VERSION 5.7 ;
  NOWIREEXTENSIONATPIN ON ;
  DIVIDERCHAR "/" ;
  BUSBITCHARS "[]" ;
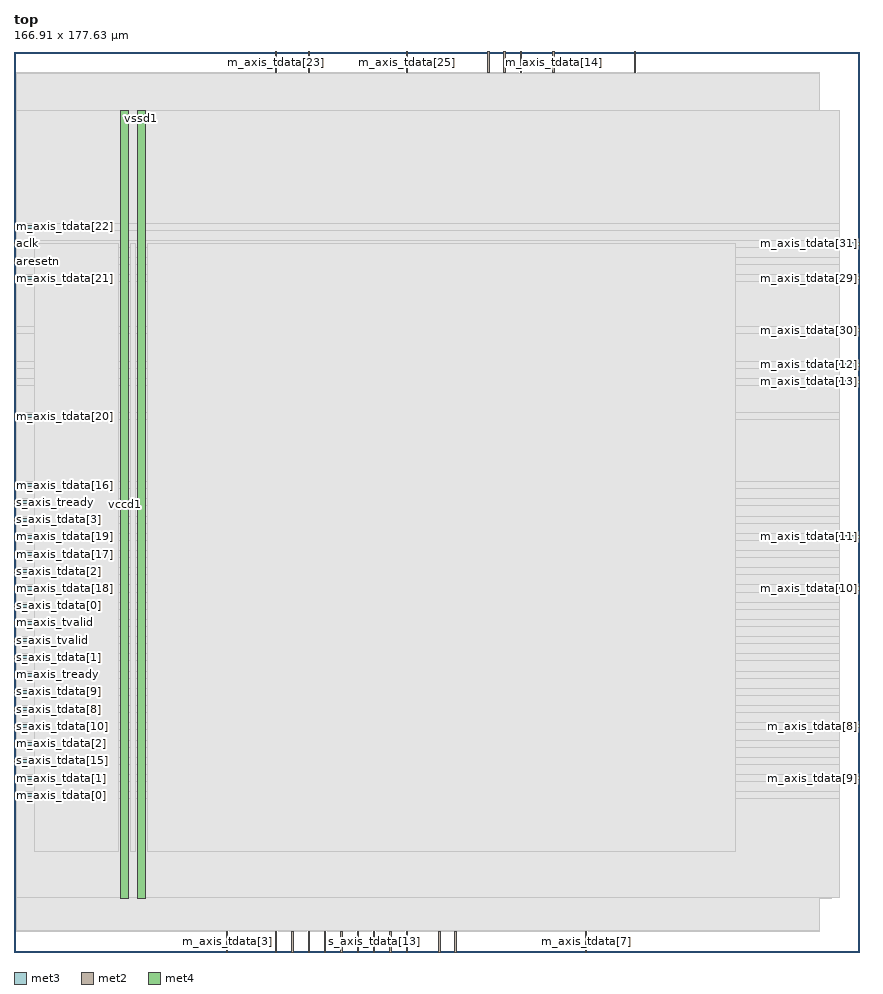
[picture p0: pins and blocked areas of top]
MACRO top
  CLASS BLOCK ;
  FOREIGN top ;
  ORIGIN 0.000 0.000 ;
  SIZE 166.910 BY 177.630 ;
  PIN aclk
    DIRECTION INPUT ;
    USE SIGNAL ;
    ANTENNAGATEAREA 1.286700 ;
    ANTENNADIFFAREA 0.434700 ;
    PORT
      LAYER met3 ;
        RECT 0.000 139.440 4.000 140.040 ;
    END
  END aclk
  PIN aresetn
    DIRECTION INPUT ;
    USE SIGNAL ;
    ANTENNAGATEAREA 0.631200 ;
    ANTENNADIFFAREA 0.434700 ;
    PORT
      LAYER met3 ;
        RECT 0.000 136.040 4.000 136.640 ;
    END
  END aresetn
  PIN m_axis_tdata[0]
    DIRECTION OUTPUT ;
    USE SIGNAL ;
    ANTENNADIFFAREA 0.445500 ;
    PORT
      LAYER met3 ;
        RECT 0.000 30.640 4.000 31.240 ;
    END
  END m_axis_tdata[0]
  PIN m_axis_tdata[10]
    DIRECTION OUTPUT ;
    USE SIGNAL ;
    ANTENNADIFFAREA 0.445500 ;
    PORT
      LAYER met3 ;
        RECT 162.910 71.440 166.910 72.040 ;
    END
  END m_axis_tdata[10]
  PIN m_axis_tdata[11]
    DIRECTION OUTPUT ;
    USE SIGNAL ;
    ANTENNADIFFAREA 0.445500 ;
    PORT
      LAYER met3 ;
        RECT 162.910 81.640 166.910 82.240 ;
    END
  END m_axis_tdata[11]
  PIN m_axis_tdata[12]
    DIRECTION OUTPUT ;
    USE SIGNAL ;
    ANTENNADIFFAREA 0.445500 ;
    PORT
      LAYER met3 ;
        RECT 162.910 115.640 166.910 116.240 ;
    END
  END m_axis_tdata[12]
  PIN m_axis_tdata[13]
    DIRECTION OUTPUT ;
    USE SIGNAL ;
    ANTENNADIFFAREA 0.445500 ;
    PORT
      LAYER met3 ;
        RECT 162.910 112.240 166.910 112.840 ;
    END
  END m_axis_tdata[13]
  PIN m_axis_tdata[14]
    DIRECTION OUTPUT ;
    USE SIGNAL ;
    ANTENNADIFFAREA 0.445500 ;
    PORT
      LAYER met2 ;
        RECT 106.350 173.630 106.630 177.630 ;
    END
  END m_axis_tdata[14]
  PIN m_axis_tdata[15]
    DIRECTION OUTPUT ;
    USE SIGNAL ;
    ANTENNADIFFAREA 0.445500 ;
    PORT
      LAYER met2 ;
        RECT 99.910 173.630 100.190 177.630 ;
    END
  END m_axis_tdata[15]
  PIN m_axis_tdata[16]
    DIRECTION OUTPUT ;
    USE SIGNAL ;
    ANTENNADIFFAREA 0.445500 ;
    PORT
      LAYER met3 ;
        RECT 0.000 91.840 4.000 92.440 ;
    END
  END m_axis_tdata[16]
  PIN m_axis_tdata[17]
    DIRECTION OUTPUT ;
    USE SIGNAL ;
    ANTENNADIFFAREA 0.445500 ;
    PORT
      LAYER met3 ;
        RECT 0.000 78.240 4.000 78.840 ;
    END
  END m_axis_tdata[17]
  PIN m_axis_tdata[18]
    DIRECTION OUTPUT ;
    USE SIGNAL ;
    ANTENNADIFFAREA 0.445500 ;
    PORT
      LAYER met3 ;
        RECT 0.000 71.440 4.000 72.040 ;
    END
  END m_axis_tdata[18]
  PIN m_axis_tdata[19]
    DIRECTION OUTPUT ;
    USE SIGNAL ;
    ANTENNADIFFAREA 0.445500 ;
    PORT
      LAYER met3 ;
        RECT 0.000 81.640 4.000 82.240 ;
    END
  END m_axis_tdata[19]
  PIN m_axis_tdata[1]
    DIRECTION OUTPUT ;
    USE SIGNAL ;
    ANTENNADIFFAREA 0.445500 ;
    PORT
      LAYER met3 ;
        RECT 0.000 34.040 4.000 34.640 ;
    END
  END m_axis_tdata[1]
  PIN m_axis_tdata[20]
    DIRECTION OUTPUT ;
    USE SIGNAL ;
    ANTENNADIFFAREA 0.445500 ;
    PORT
      LAYER met3 ;
        RECT 0.000 105.440 4.000 106.040 ;
    END
  END m_axis_tdata[20]
  PIN m_axis_tdata[21]
    DIRECTION OUTPUT ;
    USE SIGNAL ;
    ANTENNADIFFAREA 0.445500 ;
    PORT
      LAYER met3 ;
        RECT 0.000 132.640 4.000 133.240 ;
    END
  END m_axis_tdata[21]
  PIN m_axis_tdata[22]
    DIRECTION OUTPUT ;
    USE SIGNAL ;
    ANTENNADIFFAREA 0.445500 ;
    PORT
      LAYER met3 ;
        RECT 0.000 142.840 4.000 143.440 ;
    END
  END m_axis_tdata[22]
  PIN m_axis_tdata[23]
    DIRECTION OUTPUT ;
    USE SIGNAL ;
    ANTENNADIFFAREA 0.445500 ;
    PORT
      LAYER met2 ;
        RECT 51.610 173.630 51.890 177.630 ;
    END
  END m_axis_tdata[23]
  PIN m_axis_tdata[24]
    DIRECTION OUTPUT ;
    USE SIGNAL ;
    ANTENNADIFFAREA 0.445500 ;
    PORT
      LAYER met2 ;
        RECT 58.050 173.630 58.330 177.630 ;
    END
  END m_axis_tdata[24]
  PIN m_axis_tdata[25]
    DIRECTION OUTPUT ;
    USE SIGNAL ;
    ANTENNADIFFAREA 0.445500 ;
    PORT
      LAYER met2 ;
        RECT 77.370 173.630 77.650 177.630 ;
    END
  END m_axis_tdata[25]
  PIN m_axis_tdata[26]
    DIRECTION OUTPUT ;
    USE SIGNAL ;
    ANTENNADIFFAREA 0.445500 ;
    PORT
      LAYER met2 ;
        RECT 96.690 173.630 96.970 177.630 ;
    END
  END m_axis_tdata[26]
  PIN m_axis_tdata[27]
    DIRECTION OUTPUT ;
    USE SIGNAL ;
    ANTENNADIFFAREA 0.445500 ;
    PORT
      LAYER met2 ;
        RECT 93.470 173.630 93.750 177.630 ;
    END
  END m_axis_tdata[27]
  PIN m_axis_tdata[28]
    DIRECTION OUTPUT ;
    USE SIGNAL ;
    ANTENNADIFFAREA 0.445500 ;
    PORT
      LAYER met2 ;
        RECT 122.450 173.630 122.730 177.630 ;
    END
  END m_axis_tdata[28]
  PIN m_axis_tdata[29]
    DIRECTION OUTPUT ;
    USE SIGNAL ;
    ANTENNADIFFAREA 0.445500 ;
    PORT
      LAYER met3 ;
        RECT 162.910 132.640 166.910 133.240 ;
    END
  END m_axis_tdata[29]
  PIN m_axis_tdata[2]
    DIRECTION OUTPUT ;
    USE SIGNAL ;
    ANTENNADIFFAREA 0.445500 ;
    PORT
      LAYER met3 ;
        RECT 0.000 40.840 4.000 41.440 ;
    END
  END m_axis_tdata[2]
  PIN m_axis_tdata[30]
    DIRECTION OUTPUT ;
    USE SIGNAL ;
    ANTENNADIFFAREA 0.445500 ;
    PORT
      LAYER met3 ;
        RECT 162.910 122.440 166.910 123.040 ;
    END
  END m_axis_tdata[30]
  PIN m_axis_tdata[31]
    DIRECTION OUTPUT ;
    USE SIGNAL ;
    ANTENNADIFFAREA 0.445500 ;
    PORT
      LAYER met3 ;
        RECT 162.910 139.440 166.910 140.040 ;
    END
  END m_axis_tdata[31]
  PIN m_axis_tdata[3]
    DIRECTION OUTPUT ;
    USE SIGNAL ;
    ANTENNADIFFAREA 0.445500 ;
    PORT
      LAYER met2 ;
        RECT 41.950 0.000 42.230 4.000 ;
    END
  END m_axis_tdata[3]
  PIN m_axis_tdata[4]
    DIRECTION OUTPUT ;
    USE SIGNAL ;
    ANTENNADIFFAREA 0.445500 ;
    PORT
      LAYER met2 ;
        RECT 54.830 0.000 55.110 4.000 ;
    END
  END m_axis_tdata[4]
  PIN m_axis_tdata[5]
    DIRECTION OUTPUT ;
    USE SIGNAL ;
    ANTENNADIFFAREA 0.445500 ;
    PORT
      LAYER met2 ;
        RECT 64.490 0.000 64.770 4.000 ;
    END
  END m_axis_tdata[5]
  PIN m_axis_tdata[6]
    DIRECTION OUTPUT ;
    USE SIGNAL ;
    ANTENNADIFFAREA 0.445500 ;
    PORT
      LAYER met2 ;
        RECT 87.030 0.000 87.310 4.000 ;
    END
  END m_axis_tdata[6]
  PIN m_axis_tdata[7]
    DIRECTION OUTPUT ;
    USE SIGNAL ;
    ANTENNADIFFAREA 0.445500 ;
    PORT
      LAYER met2 ;
        RECT 112.790 0.000 113.070 4.000 ;
    END
  END m_axis_tdata[7]
  PIN m_axis_tdata[8]
    DIRECTION OUTPUT ;
    USE SIGNAL ;
    ANTENNADIFFAREA 0.445500 ;
    PORT
      LAYER met3 ;
        RECT 162.910 44.240 166.910 44.840 ;
    END
  END m_axis_tdata[8]
  PIN m_axis_tdata[9]
    DIRECTION OUTPUT ;
    USE SIGNAL ;
    ANTENNADIFFAREA 0.445500 ;
    PORT
      LAYER met3 ;
        RECT 162.910 34.040 166.910 34.640 ;
    END
  END m_axis_tdata[9]
  PIN m_axis_tready
    DIRECTION INPUT ;
    USE SIGNAL ;
    ANTENNAGATEAREA 0.647700 ;
    ANTENNADIFFAREA 0.434700 ;
    PORT
      LAYER met3 ;
        RECT 0.000 54.440 4.000 55.040 ;
    END
  END m_axis_tready
  PIN m_axis_tvalid
    DIRECTION OUTPUT ;
    USE SIGNAL ;
    ANTENNADIFFAREA 0.445500 ;
    PORT
      LAYER met3 ;
        RECT 0.000 64.640 4.000 65.240 ;
    END
  END m_axis_tvalid
  PIN s_axis_tdata[0]
    DIRECTION INPUT ;
    USE SIGNAL ;
    ANTENNAGATEAREA 0.631200 ;
    ANTENNADIFFAREA 0.434700 ;
    PORT
      LAYER met3 ;
        RECT 0.000 68.040 4.000 68.640 ;
    END
  END s_axis_tdata[0]
  PIN s_axis_tdata[10]
    DIRECTION INPUT ;
    USE SIGNAL ;
    ANTENNAGATEAREA 0.631200 ;
    ANTENNADIFFAREA 0.434700 ;
    PORT
      LAYER met3 ;
        RECT 0.000 44.240 4.000 44.840 ;
    END
  END s_axis_tdata[10]
  PIN s_axis_tdata[11]
    DIRECTION INPUT ;
    USE SIGNAL ;
    ANTENNAGATEAREA 0.631200 ;
    ANTENNADIFFAREA 0.434700 ;
    PORT
      LAYER met2 ;
        RECT 51.610 0.000 51.890 4.000 ;
    END
  END s_axis_tdata[11]
  PIN s_axis_tdata[12]
    DIRECTION INPUT ;
    USE SIGNAL ;
    ANTENNAGATEAREA 0.631200 ;
    ANTENNADIFFAREA 0.434700 ;
    PORT
      LAYER met2 ;
        RECT 61.270 0.000 61.550 4.000 ;
    END
  END s_axis_tdata[12]
  PIN s_axis_tdata[13]
    DIRECTION INPUT ;
    USE SIGNAL ;
    ANTENNAGATEAREA 0.631200 ;
    ANTENNADIFFAREA 0.434700 ;
    PORT
      LAYER met2 ;
        RECT 70.930 0.000 71.210 4.000 ;
    END
  END s_axis_tdata[13]
  PIN s_axis_tdata[14]
    DIRECTION INPUT ;
    USE SIGNAL ;
    ANTENNAGATEAREA 0.631200 ;
    ANTENNADIFFAREA 0.434700 ;
    PORT
      LAYER met2 ;
        RECT 74.150 0.000 74.430 4.000 ;
    END
  END s_axis_tdata[14]
  PIN s_axis_tdata[15]
    DIRECTION INPUT ;
    USE SIGNAL ;
    ANTENNAGATEAREA 0.631200 ;
    ANTENNADIFFAREA 0.434700 ;
    PORT
      LAYER met3 ;
        RECT 0.000 37.440 4.000 38.040 ;
    END
  END s_axis_tdata[15]
  PIN s_axis_tdata[1]
    DIRECTION INPUT ;
    USE SIGNAL ;
    ANTENNAGATEAREA 0.631200 ;
    ANTENNADIFFAREA 0.434700 ;
    PORT
      LAYER met3 ;
        RECT 0.000 57.840 4.000 58.440 ;
    END
  END s_axis_tdata[1]
  PIN s_axis_tdata[2]
    DIRECTION INPUT ;
    USE SIGNAL ;
    ANTENNAGATEAREA 0.631200 ;
    ANTENNADIFFAREA 0.434700 ;
    PORT
      LAYER met3 ;
        RECT 0.000 74.840 4.000 75.440 ;
    END
  END s_axis_tdata[2]
  PIN s_axis_tdata[3]
    DIRECTION INPUT ;
    USE SIGNAL ;
    ANTENNAGATEAREA 0.631200 ;
    ANTENNADIFFAREA 0.434700 ;
    PORT
      LAYER met3 ;
        RECT 0.000 85.040 4.000 85.640 ;
    END
  END s_axis_tdata[3]
  PIN s_axis_tdata[4]
    DIRECTION INPUT ;
    USE SIGNAL ;
    ANTENNAGATEAREA 0.631200 ;
    ANTENNADIFFAREA 0.434700 ;
    PORT
      LAYER met2 ;
        RECT 58.050 0.000 58.330 4.000 ;
    END
  END s_axis_tdata[4]
  PIN s_axis_tdata[5]
    DIRECTION INPUT ;
    USE SIGNAL ;
    ANTENNAGATEAREA 0.631200 ;
    ANTENNADIFFAREA 0.434700 ;
    PORT
      LAYER met2 ;
        RECT 67.710 0.000 67.990 4.000 ;
    END
  END s_axis_tdata[5]
  PIN s_axis_tdata[6]
    DIRECTION INPUT ;
    USE SIGNAL ;
    ANTENNAGATEAREA 0.631200 ;
    ANTENNADIFFAREA 0.434700 ;
    PORT
      LAYER met2 ;
        RECT 77.370 0.000 77.650 4.000 ;
    END
  END s_axis_tdata[6]
  PIN s_axis_tdata[7]
    DIRECTION INPUT ;
    USE SIGNAL ;
    ANTENNAGATEAREA 0.631200 ;
    ANTENNADIFFAREA 0.434700 ;
    PORT
      LAYER met2 ;
        RECT 83.810 0.000 84.090 4.000 ;
    END
  END s_axis_tdata[7]
  PIN s_axis_tdata[8]
    DIRECTION INPUT ;
    USE SIGNAL ;
    ANTENNAGATEAREA 0.631200 ;
    ANTENNADIFFAREA 0.434700 ;
    PORT
      LAYER met3 ;
        RECT 0.000 47.640 4.000 48.240 ;
    END
  END s_axis_tdata[8]
  PIN s_axis_tdata[9]
    DIRECTION INPUT ;
    USE SIGNAL ;
    ANTENNAGATEAREA 0.631200 ;
    ANTENNADIFFAREA 0.434700 ;
    PORT
      LAYER met3 ;
        RECT 0.000 51.040 4.000 51.640 ;
    END
  END s_axis_tdata[9]
  PIN s_axis_tready
    DIRECTION OUTPUT ;
    USE SIGNAL ;
    ANTENNADIFFAREA 0.445500 ;
    PORT
      LAYER met3 ;
        RECT 0.000 88.440 4.000 89.040 ;
    END
  END s_axis_tready
  PIN s_axis_tvalid
    DIRECTION INPUT ;
    USE SIGNAL ;
    ANTENNAGATEAREA 0.631200 ;
    ANTENNADIFFAREA 0.434700 ;
    PORT
      LAYER met3 ;
        RECT 0.000 61.240 4.000 61.840 ;
    END
  END s_axis_tvalid
  PIN vccd1
    DIRECTION INOUT ;
    USE POWER ;
    PORT
      LAYER met4 ;
        RECT 21.040 10.640 22.640 166.160 ;
    END
  END vccd1
  PIN vssd1
    DIRECTION INOUT ;
    USE GROUND ;
    PORT
      LAYER met4 ;
        RECT 24.340 10.640 25.940 166.160 ;
    END
  END vssd1
  OBS
      LAYER nwell ;
        RECT 5.330 10.795 161.190 166.110 ;
      LAYER li1 ;
        RECT 5.520 10.795 161.000 166.005 ;
      LAYER met1 ;
        RECT 0.530 10.640 161.300 166.160 ;
      LAYER met2 ;
        RECT 0.550 173.350 51.330 173.630 ;
        RECT 52.170 173.350 57.770 173.630 ;
        RECT 58.610 173.350 77.090 173.630 ;
        RECT 77.930 173.350 93.190 173.630 ;
        RECT 94.030 173.350 96.410 173.630 ;
        RECT 97.250 173.350 99.630 173.630 ;
        RECT 100.470 173.350 106.070 173.630 ;
        RECT 106.910 173.350 122.170 173.630 ;
        RECT 123.010 173.350 159.070 173.630 ;
        RECT 0.550 4.280 159.070 173.350 ;
        RECT 0.550 4.000 41.670 4.280 ;
        RECT 42.510 4.000 51.330 4.280 ;
        RECT 52.170 4.000 54.550 4.280 ;
        RECT 55.390 4.000 57.770 4.280 ;
        RECT 58.610 4.000 60.990 4.280 ;
        RECT 61.830 4.000 64.210 4.280 ;
        RECT 65.050 4.000 67.430 4.280 ;
        RECT 68.270 4.000 70.650 4.280 ;
        RECT 71.490 4.000 73.870 4.280 ;
        RECT 74.710 4.000 77.090 4.280 ;
        RECT 77.930 4.000 83.530 4.280 ;
        RECT 84.370 4.000 86.750 4.280 ;
        RECT 87.590 4.000 112.510 4.280 ;
        RECT 113.350 4.000 159.070 4.280 ;
      LAYER met3 ;
        RECT 0.525 143.840 162.910 166.085 ;
        RECT 4.400 142.440 162.910 143.840 ;
        RECT 0.525 140.440 162.910 142.440 ;
        RECT 4.400 139.040 162.510 140.440 ;
        RECT 0.525 137.040 162.910 139.040 ;
        RECT 4.400 135.640 162.910 137.040 ;
        RECT 0.525 133.640 162.910 135.640 ;
        RECT 4.400 132.240 162.510 133.640 ;
        RECT 0.525 123.440 162.910 132.240 ;
        RECT 0.525 122.040 162.510 123.440 ;
        RECT 0.525 116.640 162.910 122.040 ;
        RECT 0.525 115.240 162.510 116.640 ;
        RECT 0.525 113.240 162.910 115.240 ;
        RECT 0.525 111.840 162.510 113.240 ;
        RECT 0.525 106.440 162.910 111.840 ;
        RECT 4.400 105.040 162.910 106.440 ;
        RECT 0.525 92.840 162.910 105.040 ;
        RECT 4.400 91.440 162.910 92.840 ;
        RECT 0.525 89.440 162.910 91.440 ;
        RECT 4.400 88.040 162.910 89.440 ;
        RECT 0.525 86.040 162.910 88.040 ;
        RECT 4.400 84.640 162.910 86.040 ;
        RECT 0.525 82.640 162.910 84.640 ;
        RECT 4.400 81.240 162.510 82.640 ;
        RECT 0.525 79.240 162.910 81.240 ;
        RECT 4.400 77.840 162.910 79.240 ;
        RECT 0.525 75.840 162.910 77.840 ;
        RECT 4.400 74.440 162.910 75.840 ;
        RECT 0.525 72.440 162.910 74.440 ;
        RECT 4.400 71.040 162.510 72.440 ;
        RECT 0.525 69.040 162.910 71.040 ;
        RECT 4.400 67.640 162.910 69.040 ;
        RECT 0.525 65.640 162.910 67.640 ;
        RECT 4.400 64.240 162.910 65.640 ;
        RECT 0.525 62.240 162.910 64.240 ;
        RECT 4.400 60.840 162.910 62.240 ;
        RECT 0.525 58.840 162.910 60.840 ;
        RECT 4.400 57.440 162.910 58.840 ;
        RECT 0.525 55.440 162.910 57.440 ;
        RECT 4.400 54.040 162.910 55.440 ;
        RECT 0.525 52.040 162.910 54.040 ;
        RECT 4.400 50.640 162.910 52.040 ;
        RECT 0.525 48.640 162.910 50.640 ;
        RECT 4.400 47.240 162.910 48.640 ;
        RECT 0.525 45.240 162.910 47.240 ;
        RECT 4.400 43.840 162.510 45.240 ;
        RECT 0.525 41.840 162.910 43.840 ;
        RECT 4.400 40.440 162.910 41.840 ;
        RECT 0.525 38.440 162.910 40.440 ;
        RECT 4.400 37.040 162.910 38.440 ;
        RECT 0.525 35.040 162.910 37.040 ;
        RECT 4.400 33.640 162.510 35.040 ;
        RECT 0.525 31.640 162.910 33.640 ;
        RECT 4.400 30.240 162.910 31.640 ;
        RECT 0.525 10.715 162.910 30.240 ;
      LAYER met4 ;
        RECT 3.975 19.895 20.640 139.905 ;
        RECT 23.040 19.895 23.940 139.905 ;
        RECT 26.340 19.895 142.305 139.905 ;
  END
END top
END LIBRARY

